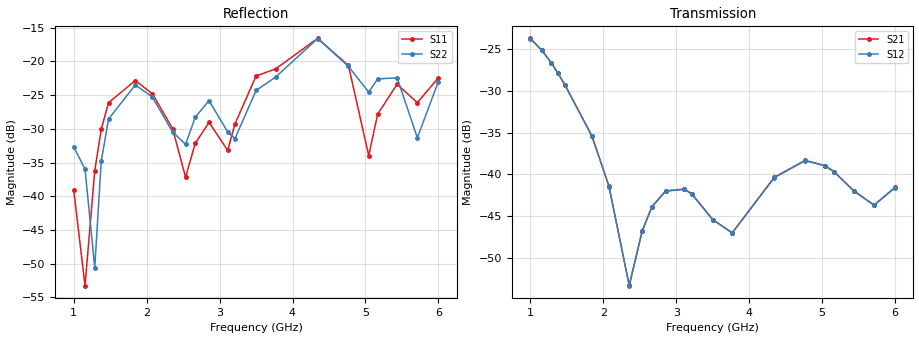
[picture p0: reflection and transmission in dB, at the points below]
!Agilent Technologies,E8364B,MY43040528,A.07.50.67
!Agilent E8364B: A.07.50.67
!Date: Sunday, March 01, 2026 16:17:22
!Correction: S11(Full 2 Port(1,2))
!S21(Full 2 Port(1,2))
!S12(Full 2 Port(1,2))
!S22(Full 2 Port(1,2))
!S2P File: Measurements: S11, S21, S12, S22:
# Hz S  dB  R 50
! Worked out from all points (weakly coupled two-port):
!   451 points, 1 GHz to 6 GHz, reference 50 ohm
!   highest |S21| = -23.72 dB at 1 GHz (marker M1); lowest = -53.3 dB at 2.356 GHz (marker M2)
!   lowest |S11| = -53.3 dB at 1.156 GHz (marker M3), VSWR 1.00, Z = 49.9 + j0.173 ohm
!   |S11| at or under -10 dB: start of sweep to end of sweep
!   |S22| runs from -50.6 to -16.5 dB; largest |S21 - S12| = 0.00029
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1e9  -39.03 33.6  -23.72 152.9  -23.76 152.9  -32.65 -0.7
1.155556e9  -53.26 126.9  -25.12 63.8  -25.15 63.8  -36.00 -2.1
1.288889e9  -36.21 -164.0  -26.65 -12.0  -26.68 -11.9  -50.58 56.9
1.377778e9  -30.07 -176.6  -27.86 -61.7  -27.90 -61.6  -34.79 106.6
1.477778e9  -26.12 160.7  -29.34 -116.5  -29.36 -116.4  -28.54 82.6
1.844444e9  -22.83 88.2  -35.40 47.3  -35.43 47.4  -23.48 -3.4
2.077778e9  -24.77 54.9  -41.40 -74.4  -41.46 -74.3  -25.26 -43.4
2.355556e9  -29.95 25.3  -53.28 -149.0  -53.32 -148.8  -30.44 -74.0
2.533333e9  -37.16 52.8  -46.75 169.1  -46.80 169.4  -32.30 -50.6
2.666667e9  -32.15 82.3  -43.85 104.2  -43.90 104.3  -28.26 -53.1
2.855556e9  -29.02 59.2  -41.97 5.7  -42.00 5.7  -25.81 -90.1
3.111111e9  -33.19 73.8  -41.76 -130.3  -41.80 -130.3  -30.45 -126.9
3.211111e9  -29.27 90.0  -42.29 177.2  -42.34 177.2  -31.43 -110.4
3.5e9  -22.15 56.4  -45.40 36.8  -45.43 36.8  -24.30 -127.4
3.766667e9  -21.11 31.4  -46.99 -66.2  -47.02 -66.2  -22.33 -156.1
4.344444e9  -16.57 -40.1  -40.34 22.2  -40.39 22.3  -16.59 110.6
4.766667e9  -20.59 -109.3  -38.32 146.1  -38.36 146.2  -20.73 37.3
5.044444e9  -33.96 -94.4  -38.96 -17.3  -38.99 -17.3  -24.55 38.2
5.166667e9  -27.83 -54.3  -39.70 -90.9  -39.74 -90.9  -22.60 32.0
5.433333e9  -23.37 -88.9  -41.95 100.4  -41.98 100.3  -22.41 -17.8
5.711111e9  -26.11 -91.5  -43.66 -96.1  -43.70 -96.0  -31.31 -17.5
6e9  -22.41 -91.0  -41.55 59.4  -41.59 59.4  -22.97 -17.1
